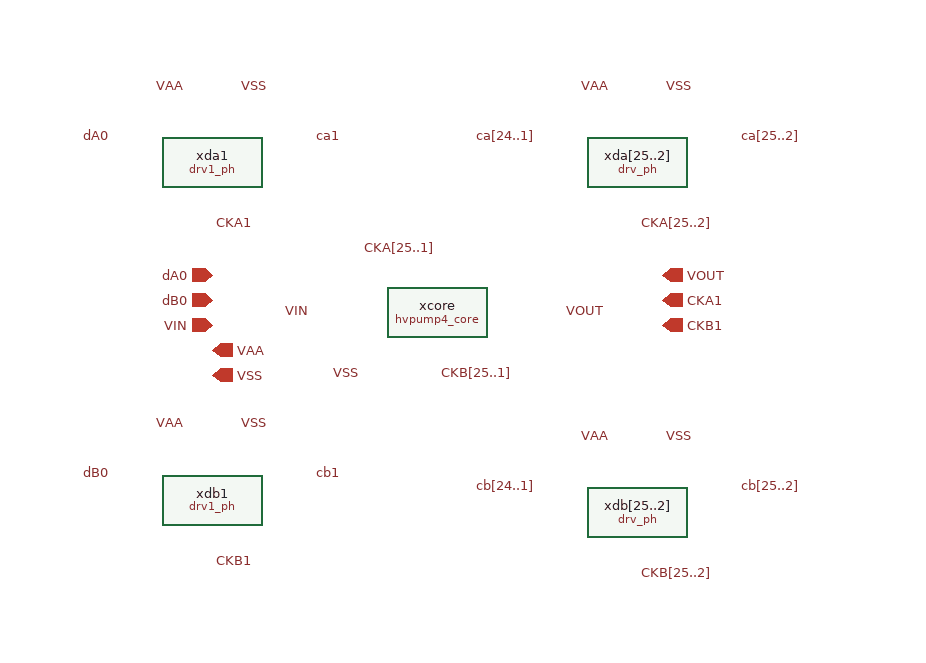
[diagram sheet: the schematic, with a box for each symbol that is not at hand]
v {xschem version=3.4.8RC file_version=1.3}
G {}
K {}
V {}
S {}
F {}
E {}
P 4 1 750 -230 {}
C {hvpump4_core.sym} 420 -250 0 0 {name=xcore}
C {drv1_ph.sym} 240 -370 0 0 {name=xda1}
C {lab_pin.sym} 320 -250 0 0 {name=p1 lab=VIN}
C {lab_pin.sym} 520 -250 0 1 {name=p2 lab=VOUT}
C {lab_pin.sym} 420 -300 0 0 {name=p3 lab=CKA[25..1]}
C {lab_pin.sym} 360 -200 0 0 {name=p4 lab=VSS}
C {lab_pin.sym} 420 -200 0 1 {name=p5 lab=CKB[25..1]}
C {lab_pin.sym} 160 -390 0 0 {name=p6 lab=dA0}
C {lab_pin.sym} 320 -390 0 1 {name=p7 lab=ca1}
C {lab_pin.sym} 240 -320 0 1 {name=p8 lab=CKA1}
C {lab_pin.sym} 260 -430 0 1 {name=p9 lab=VSS}
C {lab_pin.sym} 220 -430 0 0 {name=p10 lab=VAA}
C {drv_ph.sym} 580 -370 0 0 {name=xda[25..2]}
C {lab_pin.sym} 500 -390 0 0 {name=p11 lab=ca[24..1]}
C {lab_pin.sym} 660 -390 0 1 {name=p12 lab=ca[25..2]}
C {lab_pin.sym} 580 -320 0 1 {name=p13 lab=CKA[25..2]}
C {lab_pin.sym} 600 -430 0 1 {name=p14 lab=VSS}
C {lab_pin.sym} 560 -430 0 0 {name=p15 lab=VAA}
C {drv1_ph.sym} 240 -100 0 0 {name=xdb1}
C {lab_pin.sym} 160 -120 0 0 {name=p16 lab=dB0}
C {lab_pin.sym} 320 -120 0 1 {name=p17 lab=cb1}
C {lab_pin.sym} 240 -50 0 1 {name=p18 lab=CKB1}
C {lab_pin.sym} 260 -160 0 1 {name=p19 lab=VSS}
C {lab_pin.sym} 220 -160 0 0 {name=p20 lab=VAA}
C {drv_ph.sym} 580 -90 0 0 {name=xdb[25..2]}
C {lab_pin.sym} 500 -110 0 0 {name=p21 lab=cb[24..1]}
C {lab_pin.sym} 660 -110 0 1 {name=p22 lab=cb[25..2]}
C {lab_pin.sym} 580 -40 0 1 {name=p23 lab=CKB[25..2]}
C {lab_pin.sym} 600 -150 0 1 {name=p24 lab=VSS}
C {lab_pin.sym} 560 -150 0 0 {name=p25 lab=VAA}
C {ipin.sym} 240 -280 0 0 {name=p26 lab=dA0 sim_pinnumber=1}
C {ipin.sym} 240 -260 0 0 {name=p27 lab=dB0 sim_pinnumber=2}
C {ipin.sym} 240 -240 0 0 {name=p28 lab=VIN sim_pinnumber=3}
C {iopin.sym} 240 -220 0 1 {name=p29 lab=VAA sim_pinnumber=7}
C {iopin.sym} 240 -200 0 1 {name=p30 lab=VSS sim_pinnumber=8}
C {opin.sym} 600 -280 0 0 {name=p31 lab=VOUT sim_pinnumber=4}
C {opin.sym} 600 -260 0 0 {name=p32 lab=CKA1 sim_pinnumber=5}
C {opin.sym} 600 -240 0 0 {name=p33 lab=CKB1 sim_pinnumber=6}
